VERSION 5.7 ;
  NOWIREEXTENSIONATPIN ON ;
  DIVIDERCHAR "/" ;
  BUSBITCHARS "[]" ;
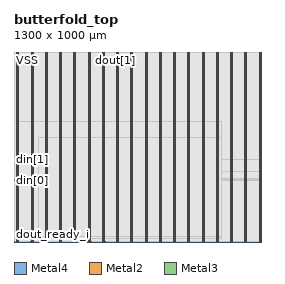
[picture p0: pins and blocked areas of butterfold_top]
MACRO butterfold_top
  CLASS BLOCK ;
  FOREIGN butterfold_top ;
  ORIGIN 0.000 0.000 ;
  SIZE 1300.000 BY 1000.000 ;
  PIN VDD
    DIRECTION INOUT ;
    USE POWER ;
    PORT
      LAYER Metal4 ;
        RECT 14.940 0.000 19.940 1000.000 ;
    END
    PORT
      LAYER Metal4 ;
        RECT 89.940 0.000 94.940 1000.000 ;
    END
    PORT
      LAYER Metal4 ;
        RECT 164.940 0.000 169.940 1000.000 ;
    END
    PORT
      LAYER Metal4 ;
        RECT 239.940 0.000 244.940 1000.000 ;
    END
    PORT
      LAYER Metal4 ;
        RECT 314.940 0.000 319.940 1000.000 ;
    END
    PORT
      LAYER Metal4 ;
        RECT 389.940 0.000 394.940 1000.000 ;
    END
    PORT
      LAYER Metal4 ;
        RECT 464.940 0.000 469.940 1000.000 ;
    END
    PORT
      LAYER Metal4 ;
        RECT 539.940 0.000 544.940 1000.000 ;
    END
    PORT
      LAYER Metal4 ;
        RECT 614.940 0.000 619.940 1000.000 ;
    END
    PORT
      LAYER Metal4 ;
        RECT 689.940 0.000 694.940 1000.000 ;
    END
    PORT
      LAYER Metal4 ;
        RECT 764.940 0.000 769.940 1000.000 ;
    END
    PORT
      LAYER Metal4 ;
        RECT 839.940 0.000 844.940 1000.000 ;
    END
    PORT
      LAYER Metal4 ;
        RECT 914.940 0.000 919.940 1000.000 ;
    END
    PORT
      LAYER Metal4 ;
        RECT 989.940 0.000 994.940 1000.000 ;
    END
    PORT
      LAYER Metal4 ;
        RECT 1064.940 0.000 1069.940 1000.000 ;
    END
    PORT
      LAYER Metal4 ;
        RECT 1139.940 0.000 1144.940 1000.000 ;
    END
    PORT
      LAYER Metal4 ;
        RECT 1214.940 0.000 1219.940 1000.000 ;
    END
    PORT
      LAYER Metal4 ;
        RECT 1289.940 0.000 1294.940 1000.000 ;
    END
  END VDD
  PIN VSS
    DIRECTION INOUT ;
    USE GROUND ;
    PORT
      LAYER Metal4 ;
        RECT 20.940 0.000 25.940 1000.000 ;
    END
    PORT
      LAYER Metal4 ;
        RECT 95.940 0.000 100.940 1000.000 ;
    END
    PORT
      LAYER Metal4 ;
        RECT 170.940 0.000 175.940 1000.000 ;
    END
    PORT
      LAYER Metal4 ;
        RECT 245.940 0.000 250.940 1000.000 ;
    END
    PORT
      LAYER Metal4 ;
        RECT 320.940 0.000 325.940 1000.000 ;
    END
    PORT
      LAYER Metal4 ;
        RECT 395.940 0.000 400.940 1000.000 ;
    END
    PORT
      LAYER Metal4 ;
        RECT 470.940 0.000 475.940 1000.000 ;
    END
    PORT
      LAYER Metal4 ;
        RECT 545.940 0.000 550.940 1000.000 ;
    END
    PORT
      LAYER Metal4 ;
        RECT 620.940 0.000 625.940 1000.000 ;
    END
    PORT
      LAYER Metal4 ;
        RECT 695.940 0.000 700.940 1000.000 ;
    END
    PORT
      LAYER Metal4 ;
        RECT 770.940 0.000 775.940 1000.000 ;
    END
    PORT
      LAYER Metal4 ;
        RECT 845.940 0.000 850.940 1000.000 ;
    END
    PORT
      LAYER Metal4 ;
        RECT 920.940 0.000 925.940 1000.000 ;
    END
    PORT
      LAYER Metal4 ;
        RECT 995.940 0.000 1000.940 1000.000 ;
    END
    PORT
      LAYER Metal4 ;
        RECT 1070.940 0.000 1075.940 1000.000 ;
    END
    PORT
      LAYER Metal4 ;
        RECT 1145.940 0.000 1150.940 1000.000 ;
    END
    PORT
      LAYER Metal4 ;
        RECT 1220.940 0.000 1225.940 1000.000 ;
    END
  END VSS
  PIN clk_i
    DIRECTION INPUT ;
    USE SIGNAL ;
    ANTENNAGATEAREA 9.476000 ;
    ANTENNADIFFAREA 0.820800 ;
    PORT
      LAYER Metal2 ;
        RECT 86.240 0.000 86.800 0.560 ;
    END
  END clk_i
  PIN din[0]
    DIRECTION INPUT ;
    USE SIGNAL ;
    ANTENNAGATEAREA 0.396000 ;
    ANTENNADIFFAREA 0.410400 ;
    PORT
      LAYER Metal3 ;
        RECT 0.000 325.920 0.560 326.480 ;
    END
  END din[0]
  PIN din[1]
    DIRECTION INPUT ;
    USE SIGNAL ;
    ANTENNAGATEAREA 0.396000 ;
    ANTENNADIFFAREA 0.410400 ;
    PORT
      LAYER Metal3 ;
        RECT 0.000 433.440 0.560 434.000 ;
    END
  END din[1]
  PIN din[2]
    DIRECTION INPUT ;
    USE SIGNAL ;
    ANTENNAGATEAREA 0.396000 ;
    ANTENNADIFFAREA 0.410400 ;
    PORT
      LAYER Metal3 ;
        RECT 0.000 324.800 0.560 325.360 ;
    END
  END din[2]
  PIN din[3]
    DIRECTION INPUT ;
    USE SIGNAL ;
    ANTENNAGATEAREA 0.396000 ;
    ANTENNADIFFAREA 0.410400 ;
    PORT
      LAYER Metal2 ;
        RECT 369.600 0.000 370.160 0.560 ;
    END
  END din[3]
  PIN din[4]
    DIRECTION INPUT ;
    USE SIGNAL ;
    ANTENNAGATEAREA 0.396000 ;
    ANTENNADIFFAREA 0.410400 ;
    PORT
      LAYER Metal2 ;
        RECT 388.640 0.000 389.200 0.560 ;
    END
  END din[4]
  PIN din[5]
    DIRECTION INPUT ;
    USE SIGNAL ;
    ANTENNAGATEAREA 0.396000 ;
    ANTENNADIFFAREA 0.410400 ;
    PORT
      LAYER Metal2 ;
        RECT 351.680 0.000 352.240 0.560 ;
    END
  END din[5]
  PIN din[6]
    DIRECTION INPUT ;
    USE SIGNAL ;
    ANTENNAGATEAREA 0.396000 ;
    ANTENNADIFFAREA 0.410400 ;
    PORT
      LAYER Metal2 ;
        RECT 387.520 0.000 388.080 0.560 ;
    END
  END din[6]
  PIN din[7]
    DIRECTION INPUT ;
    USE SIGNAL ;
    ANTENNAGATEAREA 0.396000 ;
    ANTENNADIFFAREA 0.410400 ;
    PORT
      LAYER Metal2 ;
        RECT 405.440 0.000 406.000 0.560 ;
    END
  END din[7]
  PIN din_ready_o
    DIRECTION OUTPUT ;
    USE SIGNAL ;
    ANTENNADIFFAREA 0.897600 ;
    PORT
      LAYER Metal3 ;
        RECT 0.000 329.280 0.560 329.840 ;
    END
  END din_ready_o
  PIN din_valid_i
    DIRECTION INPUT ;
    USE SIGNAL ;
    ANTENNAGATEAREA 0.396000 ;
    ANTENNADIFFAREA 0.410400 ;
    PORT
      LAYER Metal3 ;
        RECT 0.000 333.760 0.560 334.320 ;
    END
  END din_valid_i
  PIN done_irq_o
    DIRECTION OUTPUT ;
    USE SIGNAL ;
    ANTENNADIFFAREA 0.897600 ;
    PORT
      LAYER Metal3 ;
        RECT 0.000 371.840 0.560 372.400 ;
    END
  END done_irq_o
  PIN dout[0]
    DIRECTION OUTPUT ;
    USE SIGNAL ;
    ANTENNADIFFAREA 0.360800 ;
    PORT
      LAYER Metal2 ;
        RECT 558.880 999.440 559.440 1000.000 ;
    END
  END dout[0]
  PIN dout[1]
    DIRECTION OUTPUT ;
    USE SIGNAL ;
    ANTENNADIFFAREA 0.360800 ;
    PORT
      LAYER Metal2 ;
        RECT 533.120 999.440 533.680 1000.000 ;
    END
  END dout[1]
  PIN dout[2]
    DIRECTION OUTPUT ;
    USE SIGNAL ;
    ANTENNADIFFAREA 0.360800 ;
    PORT
      LAYER Metal2 ;
        RECT 549.920 999.440 550.480 1000.000 ;
    END
  END dout[2]
  PIN dout[3]
    DIRECTION OUTPUT ;
    USE SIGNAL ;
    ANTENNADIFFAREA 0.360800 ;
    PORT
      LAYER Metal2 ;
        RECT 596.960 999.440 597.520 1000.000 ;
    END
  END dout[3]
  PIN dout[4]
    DIRECTION OUTPUT ;
    USE SIGNAL ;
    ANTENNADIFFAREA 0.360800 ;
    PORT
      LAYER Metal2 ;
        RECT 525.280 999.440 525.840 1000.000 ;
    END
  END dout[4]
  PIN dout[5]
    DIRECTION OUTPUT ;
    USE SIGNAL ;
    ANTENNADIFFAREA 0.360800 ;
    PORT
      LAYER Metal2 ;
        RECT 534.240 999.440 534.800 1000.000 ;
    END
  END dout[5]
  PIN dout[6]
    DIRECTION OUTPUT ;
    USE SIGNAL ;
    ANTENNADIFFAREA 0.360800 ;
    PORT
      LAYER Metal2 ;
        RECT 532.000 999.440 532.560 1000.000 ;
    END
  END dout[6]
  PIN dout[7]
    DIRECTION OUTPUT ;
    USE SIGNAL ;
    ANTENNADIFFAREA 0.360800 ;
    PORT
      LAYER Metal2 ;
        RECT 542.080 999.440 542.640 1000.000 ;
    END
  END dout[7]
  PIN dout_ready_i
    DIRECTION INPUT ;
    USE SIGNAL ;
    PORT
      LAYER Metal2 ;
        RECT 1.120 0.000 1.680 0.560 ;
    END
  END dout_ready_i
  PIN dout_valid_o
    DIRECTION OUTPUT ;
    USE SIGNAL ;
    ANTENNADIFFAREA 0.360800 ;
    PORT
      LAYER Metal2 ;
        RECT 551.040 999.440 551.600 1000.000 ;
    END
  END dout_valid_o
  PIN rst_ni
    DIRECTION INPUT ;
    USE SIGNAL ;
    ANTENNAGATEAREA 0.396000 ;
    ANTENNADIFFAREA 0.410400 ;
    PORT
      LAYER Metal2 ;
        RECT 100.800 0.000 101.360 0.560 ;
    END
  END rst_ni
  PIN scan_en_i
    DIRECTION INPUT ;
    USE SIGNAL ;
    ANTENNAGATEAREA 0.396000 ;
    ANTENNADIFFAREA 0.410400 ;
    PORT
      LAYER Metal2 ;
        RECT 479.360 0.000 479.920 0.560 ;
    END
  END scan_en_i
  PIN scan_in_i
    DIRECTION INPUT ;
    USE SIGNAL ;
    ANTENNAGATEAREA 0.396000 ;
    ANTENNADIFFAREA 0.410400 ;
    PORT
      LAYER Metal2 ;
        RECT 480.480 0.000 481.040 0.560 ;
    END
  END scan_in_i
  PIN scan_out_o
    DIRECTION OUTPUT ;
    USE SIGNAL ;
    ANTENNADIFFAREA 0.897600 ;
    PORT
      LAYER Metal2 ;
        RECT 476.000 0.000 476.560 0.560 ;
    END
  END scan_out_o
  OBS
      LAYER Nwell ;
        RECT 0.690 3.490 1299.070 996.110 ;
      LAYER Metal1 ;
        RECT 1.120 3.620 1298.640 995.980 ;
      LAYER Metal2 ;
        RECT 2.380 999.140 524.980 999.440 ;
        RECT 526.140 999.140 531.700 999.440 ;
        RECT 535.100 999.140 541.780 999.440 ;
        RECT 542.940 999.140 549.620 999.440 ;
        RECT 551.900 999.140 558.580 999.440 ;
        RECT 559.740 999.140 596.660 999.440 ;
        RECT 597.820 999.140 1294.660 999.440 ;
        RECT 2.380 0.860 1294.660 999.140 ;
        RECT 2.380 0.090 85.940 0.860 ;
        RECT 87.100 0.090 100.500 0.860 ;
        RECT 101.660 0.090 351.380 0.860 ;
        RECT 352.540 0.090 369.300 0.860 ;
        RECT 370.460 0.090 387.220 0.860 ;
        RECT 389.500 0.090 405.140 0.860 ;
        RECT 406.300 0.090 475.700 0.860 ;
        RECT 476.860 0.090 479.060 0.860 ;
        RECT 481.340 0.090 1294.660 0.860 ;
      LAYER Metal3 ;
        RECT 0.560 434.300 1294.710 996.660 ;
        RECT 0.860 433.140 1294.710 434.300 ;
        RECT 0.560 372.700 1294.710 433.140 ;
        RECT 0.860 371.540 1294.710 372.700 ;
        RECT 0.560 334.620 1294.710 371.540 ;
        RECT 0.860 333.460 1294.710 334.620 ;
        RECT 0.560 330.140 1294.710 333.460 ;
        RECT 0.860 328.980 1294.710 330.140 ;
        RECT 0.560 326.780 1294.710 328.980 ;
        RECT 0.860 324.500 1294.710 326.780 ;
        RECT 0.560 0.140 1294.710 324.500 ;
      LAYER Metal4 ;
        RECT 5.180 16.890 14.640 632.710 ;
        RECT 20.240 16.890 20.640 632.710 ;
        RECT 26.240 16.890 89.640 632.710 ;
        RECT 95.240 16.890 95.640 632.710 ;
        RECT 101.240 16.890 164.640 632.710 ;
        RECT 170.240 16.890 170.640 632.710 ;
        RECT 176.240 16.890 239.640 632.710 ;
        RECT 245.240 16.890 245.640 632.710 ;
        RECT 251.240 16.890 314.640 632.710 ;
        RECT 320.240 16.890 320.640 632.710 ;
        RECT 326.240 16.890 389.640 632.710 ;
        RECT 395.240 16.890 395.640 632.710 ;
        RECT 401.240 16.890 464.640 632.710 ;
        RECT 470.240 16.890 470.640 632.710 ;
        RECT 476.240 16.890 539.640 632.710 ;
        RECT 545.240 16.890 545.640 632.710 ;
        RECT 551.240 16.890 614.640 632.710 ;
        RECT 620.240 16.890 620.640 632.710 ;
        RECT 626.240 16.890 689.640 632.710 ;
        RECT 695.240 16.890 695.640 632.710 ;
        RECT 701.240 16.890 764.640 632.710 ;
        RECT 770.240 16.890 770.640 632.710 ;
        RECT 776.240 16.890 839.640 632.710 ;
        RECT 845.240 16.890 845.640 632.710 ;
        RECT 851.240 16.890 914.640 632.710 ;
        RECT 920.240 16.890 920.640 632.710 ;
        RECT 926.240 16.890 989.640 632.710 ;
        RECT 995.240 16.890 995.640 632.710 ;
        RECT 1001.240 16.890 1064.640 632.710 ;
        RECT 1070.240 16.890 1070.640 632.710 ;
        RECT 1076.240 16.890 1092.980 632.710 ;
      LAYER Metal5 ;
        RECT 127.740 28.130 1093.060 547.870 ;
  END
END butterfold_top
END LIBRARY

